VERSION 5.7 ;
  NOWIREEXTENSIONATPIN ON ;
  DIVIDERCHAR "/" ;
  BUSBITCHARS "[]" ;
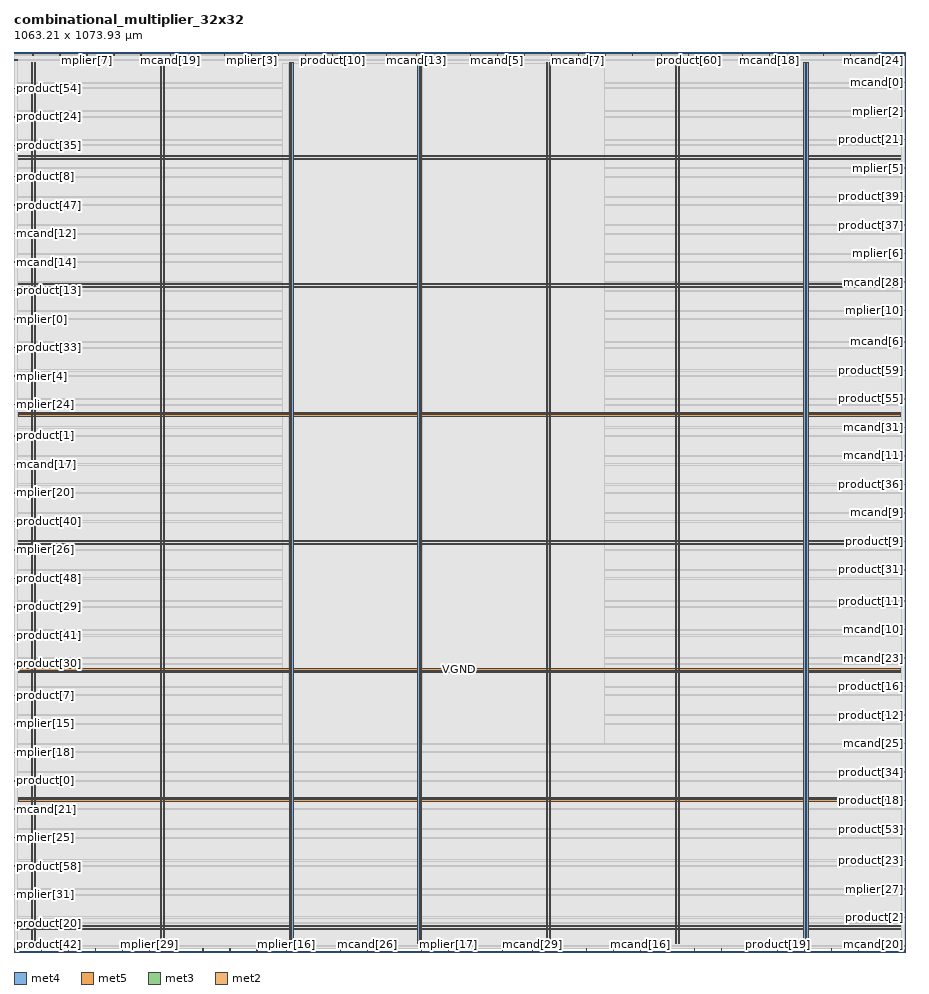
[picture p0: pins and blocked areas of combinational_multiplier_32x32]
MACRO combinational_multiplier_32x32
  CLASS BLOCK ;
  FOREIGN combinational_multiplier_32x32 ;
  ORIGIN 0.000 0.000 ;
  SIZE 1063.210 BY 1073.930 ;
  PIN VGND
    DIRECTION INOUT ;
    USE GROUND ;
    PORT
      LAYER met4 ;
        RECT 24.340 10.640 25.940 1061.040 ;
    END
    PORT
      LAYER met4 ;
        RECT 177.940 10.640 179.540 1061.040 ;
    END
    PORT
      LAYER met4 ;
        RECT 331.540 10.640 333.140 1061.040 ;
    END
    PORT
      LAYER met4 ;
        RECT 485.140 10.640 486.740 1061.040 ;
    END
    PORT
      LAYER met4 ;
        RECT 638.740 10.640 640.340 1061.040 ;
    END
    PORT
      LAYER met4 ;
        RECT 792.340 10.640 793.940 1061.040 ;
    END
    PORT
      LAYER met4 ;
        RECT 945.940 10.640 947.540 1061.040 ;
    END
    PORT
      LAYER met5 ;
        RECT 5.280 30.030 1057.780 31.630 ;
    END
    PORT
      LAYER met5 ;
        RECT 5.280 183.210 1057.780 184.810 ;
    END
    PORT
      LAYER met5 ;
        RECT 5.280 336.390 1057.780 337.990 ;
    END
    PORT
      LAYER met5 ;
        RECT 5.280 489.570 1057.780 491.170 ;
    END
    PORT
      LAYER met5 ;
        RECT 5.280 642.750 1057.780 644.350 ;
    END
    PORT
      LAYER met5 ;
        RECT 5.280 795.930 1057.780 797.530 ;
    END
    PORT
      LAYER met5 ;
        RECT 5.280 949.110 1057.780 950.710 ;
    END
  END VGND
  PIN VPWR
    DIRECTION INOUT ;
    USE POWER ;
    PORT
      LAYER met4 ;
        RECT 21.040 10.640 22.640 1061.040 ;
    END
    PORT
      LAYER met4 ;
        RECT 174.640 10.640 176.240 1061.040 ;
    END
    PORT
      LAYER met4 ;
        RECT 328.240 10.640 329.840 1061.040 ;
    END
    PORT
      LAYER met4 ;
        RECT 481.840 10.640 483.440 1061.040 ;
    END
    PORT
      LAYER met4 ;
        RECT 635.440 10.640 637.040 1061.040 ;
    END
    PORT
      LAYER met4 ;
        RECT 789.040 10.640 790.640 1061.040 ;
    END
    PORT
      LAYER met4 ;
        RECT 942.640 10.640 944.240 1061.040 ;
    END
    PORT
      LAYER met5 ;
        RECT 5.280 26.730 1057.780 28.330 ;
    END
    PORT
      LAYER met5 ;
        RECT 5.280 179.910 1057.780 181.510 ;
    END
    PORT
      LAYER met5 ;
        RECT 5.280 333.090 1057.780 334.690 ;
    END
    PORT
      LAYER met5 ;
        RECT 5.280 486.270 1057.780 487.870 ;
    END
    PORT
      LAYER met5 ;
        RECT 5.280 639.450 1057.780 641.050 ;
    END
    PORT
      LAYER met5 ;
        RECT 5.280 792.630 1057.780 794.230 ;
    END
    PORT
      LAYER met5 ;
        RECT 5.280 945.810 1057.780 947.410 ;
    END
  END VPWR
  PIN mcand[0]
    DIRECTION INPUT ;
    USE SIGNAL ;
    ANTENNAGATEAREA 0.990000 ;
    PORT
      LAYER met3 ;
        RECT 1059.210 1037.040 1063.210 1037.640 ;
    END
  END mcand[0]
  PIN mcand[10]
    DIRECTION INPUT ;
    USE SIGNAL ;
    ANTENNAGATEAREA 0.742500 ;
    PORT
      LAYER met3 ;
        RECT 1059.210 384.240 1063.210 384.840 ;
    END
  END mcand[10]
  PIN mcand[11]
    DIRECTION INPUT ;
    USE SIGNAL ;
    ANTENNAGATEAREA 0.742500 ;
    PORT
      LAYER met3 ;
        RECT 1059.210 591.640 1063.210 592.240 ;
    END
  END mcand[11]
  PIN mcand[12]
    DIRECTION INPUT ;
    USE SIGNAL ;
    ANTENNAGATEAREA 0.426000 ;
    PORT
      LAYER met3 ;
        RECT 0.000 856.840 4.000 857.440 ;
    END
  END mcand[12]
  PIN mcand[13]
    DIRECTION INPUT ;
    USE SIGNAL ;
    ANTENNAGATEAREA 0.742500 ;
    PORT
      LAYER met2 ;
        RECT 479.870 1069.930 480.150 1073.930 ;
    END
  END mcand[13]
  PIN mcand[14]
    DIRECTION INPUT ;
    USE SIGNAL ;
    ANTENNAGATEAREA 0.742500 ;
    PORT
      LAYER met3 ;
        RECT 0.000 822.840 4.000 823.440 ;
    END
  END mcand[14]
  PIN mcand[15]
    DIRECTION INPUT ;
    USE SIGNAL ;
    ANTENNAGATEAREA 0.247500 ;
    PORT
      LAYER met2 ;
        RECT 512.070 1069.930 512.350 1073.930 ;
    END
  END mcand[15]
  PIN mcand[16]
    DIRECTION INPUT ;
    USE SIGNAL ;
    ANTENNAGATEAREA 0.426000 ;
    PORT
      LAYER met2 ;
        RECT 747.130 0.000 747.410 4.000 ;
    END
  END mcand[16]
  PIN mcand[17]
    DIRECTION INPUT ;
    USE SIGNAL ;
    ANTENNAGATEAREA 0.495000 ;
    PORT
      LAYER met3 ;
        RECT 0.000 581.440 4.000 582.040 ;
    END
  END mcand[17]
  PIN mcand[18]
    DIRECTION INPUT ;
    USE SIGNAL ;
    ANTENNAGATEAREA 0.742500 ;
    PORT
      LAYER met2 ;
        RECT 901.690 1069.930 901.970 1073.930 ;
    END
  END mcand[18]
  PIN mcand[19]
    DIRECTION INPUT ;
    USE SIGNAL ;
    ANTENNAGATEAREA 0.742500 ;
    PORT
      LAYER met2 ;
        RECT 186.850 1069.930 187.130 1073.930 ;
    END
  END mcand[19]
  PIN mcand[1]
    DIRECTION INPUT ;
    USE SIGNAL ;
    ANTENNAGATEAREA 0.742500 ;
    PORT
      LAYER met2 ;
        RECT 933.890 1069.930 934.170 1073.930 ;
    END
  END mcand[1]
  PIN mcand[20]
    DIRECTION INPUT ;
    USE SIGNAL ;
    ANTENNAGATEAREA 0.852000 ;
    PORT
      LAYER met2 ;
        RECT 1040.150 0.000 1040.430 4.000 ;
    END
  END mcand[20]
  PIN mcand[21]
    DIRECTION INPUT ;
    USE SIGNAL ;
    ANTENNAGATEAREA 0.852000 ;
    PORT
      LAYER met3 ;
        RECT 0.000 170.040 4.000 170.640 ;
    END
  END mcand[21]
  PIN mcand[22]
    DIRECTION INPUT ;
    USE SIGNAL ;
    ANTENNAGATEAREA 0.426000 ;
    PORT
      LAYER met2 ;
        RECT 257.690 0.000 257.970 4.000 ;
    END
  END mcand[22]
  PIN mcand[23]
    DIRECTION INPUT ;
    USE SIGNAL ;
    ANTENNAGATEAREA 0.742500 ;
    PORT
      LAYER met3 ;
        RECT 1059.210 350.240 1063.210 350.840 ;
    END
  END mcand[23]
  PIN mcand[24]
    DIRECTION INPUT ;
    USE SIGNAL ;
    ANTENNAGATEAREA 0.742500 ;
    PORT
      LAYER met2 ;
        RECT 1062.690 1069.930 1062.970 1073.930 ;
    END
  END mcand[24]
  PIN mcand[25]
    DIRECTION INPUT ;
    USE SIGNAL ;
    ANTENNAGATEAREA 0.495000 ;
    PORT
      LAYER met3 ;
        RECT 1059.210 248.240 1063.210 248.840 ;
    END
  END mcand[25]
  PIN mcand[26]
    DIRECTION INPUT ;
    USE SIGNAL ;
    ANTENNAGATEAREA 0.852000 ;
    PORT
      LAYER met2 ;
        RECT 421.910 0.000 422.190 4.000 ;
    END
  END mcand[26]
  PIN mcand[27]
    DIRECTION INPUT ;
    USE SIGNAL ;
    ANTENNAGATEAREA 0.247500 ;
    PORT
      LAYER met2 ;
        RECT 444.450 1069.930 444.730 1073.930 ;
    END
  END mcand[27]
  PIN mcand[28]
    DIRECTION INPUT ;
    USE SIGNAL ;
    ANTENNAGATEAREA 0.247500 ;
    PORT
      LAYER met3 ;
        RECT 1059.210 799.040 1063.210 799.640 ;
    END
  END mcand[28]
  PIN mcand[29]
    DIRECTION INPUT ;
    USE SIGNAL ;
    ANTENNAGATEAREA 0.742500 ;
    PORT
      LAYER met2 ;
        RECT 618.330 0.000 618.610 4.000 ;
    END
  END mcand[29]
  PIN mcand[2]
    DIRECTION INPUT ;
    USE SIGNAL ;
    ANTENNAGATEAREA 0.247500 ;
    PORT
      LAYER met2 ;
        RECT 289.890 0.000 290.170 4.000 ;
    END
  END mcand[2]
  PIN mcand[30]
    DIRECTION INPUT ;
    USE SIGNAL ;
    ANTENNAGATEAREA 0.213000 ;
    PORT
      LAYER met2 ;
        RECT 251.250 1069.930 251.530 1073.930 ;
    END
  END mcand[30]
  PIN mcand[31]
    DIRECTION INPUT ;
    USE SIGNAL ;
    ANTENNAGATEAREA 0.213000 ;
    PORT
      LAYER met3 ;
        RECT 1059.210 625.640 1063.210 626.240 ;
    END
  END mcand[31]
  PIN mcand[3]
    DIRECTION INPUT ;
    USE SIGNAL ;
    ANTENNAGATEAREA 0.495000 ;
    PORT
      LAYER met2 ;
        RECT 650.530 0.000 650.810 4.000 ;
    END
  END mcand[3]
  PIN mcand[4]
    DIRECTION INPUT ;
    USE SIGNAL ;
    ANTENNAGATEAREA 0.990000 ;
    PORT
      LAYER met2 ;
        RECT 998.290 1069.930 998.570 1073.930 ;
    END
  END mcand[4]
  PIN mcand[5]
    DIRECTION INPUT ;
    USE SIGNAL ;
    ANTENNAGATEAREA 0.247500 ;
    PORT
      LAYER met2 ;
        RECT 576.470 1069.930 576.750 1073.930 ;
    END
  END mcand[5]
  PIN mcand[6]
    DIRECTION INPUT ;
    USE SIGNAL ;
    ANTENNAGATEAREA 0.990000 ;
    PORT
      LAYER met3 ;
        RECT 1059.210 727.640 1063.210 728.240 ;
    END
  END mcand[6]
  PIN mcand[7]
    DIRECTION INPUT ;
    USE SIGNAL ;
    ANTENNAGATEAREA 0.990000 ;
    PORT
      LAYER met2 ;
        RECT 673.070 1069.930 673.350 1073.930 ;
    END
  END mcand[7]
  PIN mcand[8]
    DIRECTION INPUT ;
    USE SIGNAL ;
    ANTENNAGATEAREA 0.852000 ;
    PORT
      LAYER met2 ;
        RECT 1007.950 0.000 1008.230 4.000 ;
    END
  END mcand[8]
  PIN mcand[9]
    DIRECTION INPUT ;
    USE SIGNAL ;
    ANTENNAGATEAREA 0.495000 ;
    PORT
      LAYER met3 ;
        RECT 1059.210 523.640 1063.210 524.240 ;
    END
  END mcand[9]
  PIN mplier[0]
    DIRECTION INPUT ;
    USE SIGNAL ;
    ANTENNAGATEAREA 0.742500 ;
    PORT
      LAYER met3 ;
        RECT 0.000 754.840 4.000 755.440 ;
    END
  END mplier[0]
  PIN mplier[10]
    DIRECTION INPUT ;
    USE SIGNAL ;
    ANTENNAGATEAREA 0.742500 ;
    PORT
      LAYER met3 ;
        RECT 1059.210 765.040 1063.210 765.640 ;
    END
  END mplier[10]
  PIN mplier[11]
    DIRECTION INPUT ;
    USE SIGNAL ;
    ANTENNAGATEAREA 0.742500 ;
    PORT
      LAYER met2 ;
        RECT 454.110 0.000 454.390 4.000 ;
    END
  END mplier[11]
  PIN mplier[12]
    DIRECTION INPUT ;
    USE SIGNAL ;
    ANTENNAGATEAREA 0.495000 ;
    PORT
      LAYER met2 ;
        RECT 1030.490 1069.930 1030.770 1073.930 ;
    END
  END mplier[12]
  PIN mplier[13]
    DIRECTION INPUT ;
    USE SIGNAL ;
    ANTENNAGATEAREA 0.742500 ;
    PORT
      LAYER met2 ;
        RECT 875.930 0.000 876.210 4.000 ;
    END
  END mplier[13]
  PIN mplier[14]
    DIRECTION INPUT ;
    USE SIGNAL ;
    ANTENNAGATEAREA 0.742500 ;
    PORT
      LAYER met2 ;
        RECT 811.530 0.000 811.810 4.000 ;
    END
  END mplier[14]
  PIN mplier[15]
    DIRECTION INPUT ;
    USE SIGNAL ;
    ANTENNAGATEAREA 0.247500 ;
    PORT
      LAYER met3 ;
        RECT 0.000 272.040 4.000 272.640 ;
    END
  END mplier[15]
  PIN mplier[16]
    DIRECTION INPUT ;
    USE SIGNAL ;
    ANTENNAGATEAREA 0.426000 ;
    PORT
      LAYER met2 ;
        RECT 325.310 0.000 325.590 4.000 ;
    END
  END mplier[16]
  PIN mplier[17]
    DIRECTION INPUT ;
    USE SIGNAL ;
    ANTENNAGATEAREA 0.247500 ;
    PORT
      LAYER met2 ;
        RECT 518.510 0.000 518.790 4.000 ;
    END
  END mplier[17]
  PIN mplier[18]
    DIRECTION INPUT ;
    USE SIGNAL ;
    ANTENNAGATEAREA 0.426000 ;
    PORT
      LAYER met3 ;
        RECT 0.000 238.040 4.000 238.640 ;
    END
  END mplier[18]
  PIN mplier[19]
    DIRECTION INPUT ;
    USE SIGNAL ;
    ANTENNAGATEAREA 0.495000 ;
    PORT
      LAYER met2 ;
        RECT 608.670 1069.930 608.950 1073.930 ;
    END
  END mplier[19]
  PIN mplier[1]
    DIRECTION INPUT ;
    USE SIGNAL ;
    ANTENNAGATEAREA 0.742500 ;
    PORT
      LAYER met2 ;
        RECT 32.290 0.000 32.570 4.000 ;
    END
  END mplier[1]
  PIN mplier[20]
    DIRECTION INPUT ;
    USE SIGNAL ;
    ANTENNAGATEAREA 0.247500 ;
    PORT
      LAYER met3 ;
        RECT 0.000 547.440 4.000 548.040 ;
    END
  END mplier[20]
  PIN mplier[21]
    DIRECTION INPUT ;
    USE SIGNAL ;
    ANTENNAGATEAREA 0.742500 ;
    PORT
      LAYER met2 ;
        RECT 119.230 1069.930 119.510 1073.930 ;
    END
  END mplier[21]
  PIN mplier[22]
    DIRECTION INPUT ;
    USE SIGNAL ;
    ANTENNAGATEAREA 0.742500 ;
    PORT
      LAYER met2 ;
        RECT 737.470 1069.930 737.750 1073.930 ;
    END
  END mplier[22]
  PIN mplier[23]
    DIRECTION INPUT ;
    USE SIGNAL ;
    ANTENNAGATEAREA 0.247500 ;
    PORT
      LAYER met2 ;
        RECT 315.650 1069.930 315.930 1073.930 ;
    END
  END mplier[23]
  PIN mplier[24]
    DIRECTION INPUT ;
    USE SIGNAL ;
    ANTENNAGATEAREA 0.247500 ;
    PORT
      LAYER met3 ;
        RECT 0.000 652.840 4.000 653.440 ;
    END
  END mplier[24]
  PIN mplier[25]
    DIRECTION INPUT ;
    USE SIGNAL ;
    ANTENNAGATEAREA 0.426000 ;
    PORT
      LAYER met3 ;
        RECT 0.000 136.040 4.000 136.640 ;
    END
  END mplier[25]
  PIN mplier[26]
    DIRECTION INPUT ;
    USE SIGNAL ;
    ANTENNAGATEAREA 0.426000 ;
    PORT
      LAYER met3 ;
        RECT 0.000 479.440 4.000 480.040 ;
    END
  END mplier[26]
  PIN mplier[27]
    DIRECTION INPUT ;
    USE SIGNAL ;
    ANTENNAGATEAREA 0.742500 ;
    PORT
      LAYER met3 ;
        RECT 1059.210 74.840 1063.210 75.440 ;
    END
  END mplier[27]
  PIN mplier[28]
    DIRECTION INPUT ;
    USE SIGNAL ;
    ANTENNAGATEAREA 0.495000 ;
    PORT
      LAYER met2 ;
        RECT 389.710 0.000 389.990 4.000 ;
    END
  END mplier[28]
  PIN mplier[29]
    DIRECTION INPUT ;
    USE SIGNAL ;
    ANTENNAGATEAREA 0.247500 ;
    PORT
      LAYER met2 ;
        RECT 161.090 0.000 161.370 4.000 ;
    END
  END mplier[29]
  PIN mplier[2]
    DIRECTION INPUT ;
    USE SIGNAL ;
    ANTENNAGATEAREA 0.742500 ;
    PORT
      LAYER met3 ;
        RECT 1059.210 1003.040 1063.210 1003.640 ;
    END
  END mplier[2]
  PIN mplier[30]
    DIRECTION INPUT ;
    USE SIGNAL ;
    ANTENNAGATEAREA 0.742500 ;
    PORT
      LAYER met3 ;
        RECT 0.000 1064.240 4.000 1064.840 ;
    END
  END mplier[30]
  PIN mplier[31]
    DIRECTION INPUT ;
    USE SIGNAL ;
    ANTENNAGATEAREA 0.426000 ;
    PORT
      LAYER met3 ;
        RECT 0.000 68.040 4.000 68.640 ;
    END
  END mplier[31]
  PIN mplier[3]
    DIRECTION INPUT ;
    USE SIGNAL ;
    ANTENNAGATEAREA 0.742500 ;
    PORT
      LAYER met2 ;
        RECT 283.450 1069.930 283.730 1073.930 ;
    END
  END mplier[3]
  PIN mplier[4]
    DIRECTION INPUT ;
    USE SIGNAL ;
    ANTENNAGATEAREA 0.426000 ;
    PORT
      LAYER met3 ;
        RECT 0.000 686.840 4.000 687.440 ;
    END
  END mplier[4]
  PIN mplier[5]
    DIRECTION INPUT ;
    USE SIGNAL ;
    ANTENNAGATEAREA 0.426000 ;
    PORT
      LAYER met3 ;
        RECT 1059.210 935.040 1063.210 935.640 ;
    END
  END mplier[5]
  PIN mplier[6]
    DIRECTION INPUT ;
    USE SIGNAL ;
    ANTENNAGATEAREA 0.247500 ;
    PORT
      LAYER met3 ;
        RECT 1059.210 833.040 1063.210 833.640 ;
    END
  END mplier[6]
  PIN mplier[7]
    DIRECTION INPUT ;
    USE SIGNAL ;
    ANTENNAGATEAREA 0.742500 ;
    PORT
      LAYER met2 ;
        RECT 87.030 1069.930 87.310 1073.930 ;
    END
  END mplier[7]
  PIN mplier[8]
    DIRECTION INPUT ;
    USE SIGNAL ;
    ANTENNAGATEAREA 0.495000 ;
    PORT
      LAYER met2 ;
        RECT 151.430 1069.930 151.710 1073.930 ;
    END
  END mplier[8]
  PIN mplier[9]
    DIRECTION INPUT ;
    USE SIGNAL ;
    ANTENNAGATEAREA 0.852000 ;
    PORT
      LAYER met2 ;
        RECT 128.890 0.000 129.170 4.000 ;
    END
  END mplier[9]
  PIN product[0]
    DIRECTION OUTPUT TRISTATE ;
    USE SIGNAL ;
    ANTENNADIFFAREA 0.795200 ;
    PORT
      LAYER met3 ;
        RECT 0.000 204.040 4.000 204.640 ;
    END
  END product[0]
  PIN product[10]
    DIRECTION OUTPUT TRISTATE ;
    USE SIGNAL ;
    ANTENNADIFFAREA 0.795200 ;
    PORT
      LAYER met2 ;
        RECT 380.050 1069.930 380.330 1073.930 ;
    END
  END product[10]
  PIN product[11]
    DIRECTION OUTPUT TRISTATE ;
    USE SIGNAL ;
    ANTENNADIFFAREA 0.795200 ;
    PORT
      LAYER met3 ;
        RECT 1059.210 418.240 1063.210 418.840 ;
    END
  END product[11]
  PIN product[12]
    DIRECTION OUTPUT TRISTATE ;
    USE SIGNAL ;
    ANTENNADIFFAREA 0.795200 ;
    PORT
      LAYER met3 ;
        RECT 1059.210 282.240 1063.210 282.840 ;
    END
  END product[12]
  PIN product[13]
    DIRECTION OUTPUT TRISTATE ;
    USE SIGNAL ;
    ANTENNADIFFAREA 0.795200 ;
    PORT
      LAYER met3 ;
        RECT 0.000 788.840 4.000 789.440 ;
    END
  END product[13]
  PIN product[14]
    DIRECTION OUTPUT TRISTATE ;
    USE SIGNAL ;
    ANTENNADIFFAREA 0.795200 ;
    PORT
      LAYER met2 ;
        RECT 412.250 1069.930 412.530 1073.930 ;
    END
  END product[14]
  PIN product[15]
    DIRECTION OUTPUT TRISTATE ;
    USE SIGNAL ;
    ANTENNADIFFAREA 0.795200 ;
    PORT
      LAYER met3 ;
        RECT 1059.210 6.840 1063.210 7.440 ;
    END
  END product[15]
  PIN product[16]
    DIRECTION OUTPUT TRISTATE ;
    USE SIGNAL ;
    ANTENNADIFFAREA 0.795200 ;
    PORT
      LAYER met3 ;
        RECT 1059.210 316.240 1063.210 316.840 ;
    END
  END product[16]
  PIN product[17]
    DIRECTION OUTPUT TRISTATE ;
    USE SIGNAL ;
    ANTENNADIFFAREA 0.795200 ;
    PORT
      LAYER met2 ;
        RECT 837.290 1069.930 837.570 1073.930 ;
    END
  END product[17]
  PIN product[18]
    DIRECTION OUTPUT TRISTATE ;
    USE SIGNAL ;
    ANTENNADIFFAREA 0.795200 ;
    PORT
      LAYER met3 ;
        RECT 1059.210 180.240 1063.210 180.840 ;
    END
  END product[18]
  PIN product[19]
    DIRECTION OUTPUT TRISTATE ;
    USE SIGNAL ;
    ANTENNADIFFAREA 0.795200 ;
    PORT
      LAYER met2 ;
        RECT 911.350 0.000 911.630 4.000 ;
    END
  END product[19]
  PIN product[1]
    DIRECTION OUTPUT TRISTATE ;
    USE SIGNAL ;
    ANTENNADIFFAREA 0.795200 ;
    PORT
      LAYER met3 ;
        RECT 0.000 615.440 4.000 616.040 ;
    END
  END product[1]
  PIN product[20]
    DIRECTION OUTPUT TRISTATE ;
    USE SIGNAL ;
    ANTENNADIFFAREA 0.795200 ;
    PORT
      LAYER met3 ;
        RECT 0.000 34.040 4.000 34.640 ;
    END
  END product[20]
  PIN product[21]
    DIRECTION OUTPUT TRISTATE ;
    USE SIGNAL ;
    ANTENNADIFFAREA 0.795200 ;
    PORT
      LAYER met3 ;
        RECT 1059.210 969.040 1063.210 969.640 ;
    END
  END product[21]
  PIN product[22]
    DIRECTION OUTPUT TRISTATE ;
    USE SIGNAL ;
    ANTENNADIFFAREA 0.795200 ;
    PORT
      LAYER met2 ;
        RECT 225.490 0.000 225.770 4.000 ;
    END
  END product[22]
  PIN product[23]
    DIRECTION OUTPUT TRISTATE ;
    USE SIGNAL ;
    ANTENNADIFFAREA 0.795200 ;
    PORT
      LAYER met3 ;
        RECT 1059.210 108.840 1063.210 109.440 ;
    END
  END product[23]
  PIN product[24]
    DIRECTION OUTPUT TRISTATE ;
    USE SIGNAL ;
    ANTENNADIFFAREA 0.795200 ;
    PORT
      LAYER met3 ;
        RECT 0.000 996.240 4.000 996.840 ;
    END
  END product[24]
  PIN product[25]
    DIRECTION OUTPUT TRISTATE ;
    USE SIGNAL ;
    ANTENNADIFFAREA 0.795200 ;
    PORT
      LAYER met2 ;
        RECT 975.750 0.000 976.030 4.000 ;
    END
  END product[25]
  PIN product[26]
    DIRECTION OUTPUT TRISTATE ;
    USE SIGNAL ;
    ANTENNADIFFAREA 0.795200 ;
    PORT
      LAYER met2 ;
        RECT 544.270 1069.930 544.550 1073.930 ;
    END
  END product[26]
  PIN product[27]
    DIRECTION OUTPUT TRISTATE ;
    USE SIGNAL ;
    ANTENNADIFFAREA 0.795200 ;
    PORT
      LAYER met2 ;
        RECT 779.330 0.000 779.610 4.000 ;
    END
  END product[27]
  PIN product[28]
    DIRECTION OUTPUT TRISTATE ;
    USE SIGNAL ;
    ANTENNADIFFAREA 0.795200 ;
    PORT
      LAYER met2 ;
        RECT 96.690 0.000 96.970 4.000 ;
    END
  END product[28]
  PIN product[29]
    DIRECTION OUTPUT TRISTATE ;
    USE SIGNAL ;
    ANTENNADIFFAREA 0.795200 ;
    PORT
      LAYER met3 ;
        RECT 0.000 411.440 4.000 412.040 ;
    END
  END product[29]
  PIN product[2]
    DIRECTION OUTPUT TRISTATE ;
    USE SIGNAL ;
    ANTENNADIFFAREA 0.795200 ;
    PORT
      LAYER met3 ;
        RECT 1059.210 40.840 1063.210 41.440 ;
    END
  END product[2]
  PIN product[30]
    DIRECTION OUTPUT TRISTATE ;
    USE SIGNAL ;
    ANTENNADIFFAREA 0.795200 ;
    PORT
      LAYER met3 ;
        RECT 0.000 343.440 4.000 344.040 ;
    END
  END product[30]
  PIN product[31]
    DIRECTION OUTPUT TRISTATE ;
    USE SIGNAL ;
    ANTENNADIFFAREA 0.795200 ;
    PORT
      LAYER met3 ;
        RECT 1059.210 455.640 1063.210 456.240 ;
    END
  END product[31]
  PIN product[32]
    DIRECTION OUTPUT TRISTATE ;
    USE SIGNAL ;
    ANTENNADIFFAREA 0.795200 ;
    PORT
      LAYER met2 ;
        RECT 843.730 0.000 844.010 4.000 ;
    END
  END product[32]
  PIN product[33]
    DIRECTION OUTPUT TRISTATE ;
    USE SIGNAL ;
    ANTENNADIFFAREA 0.795200 ;
    PORT
      LAYER met3 ;
        RECT 0.000 720.840 4.000 721.440 ;
    END
  END product[33]
  PIN product[34]
    DIRECTION OUTPUT TRISTATE ;
    USE SIGNAL ;
    ANTENNADIFFAREA 0.795200 ;
    PORT
      LAYER met3 ;
        RECT 1059.210 214.240 1063.210 214.840 ;
    END
  END product[34]
  PIN product[35]
    DIRECTION OUTPUT TRISTATE ;
    USE SIGNAL ;
    ANTENNADIFFAREA 0.795200 ;
    PORT
      LAYER met3 ;
        RECT 0.000 962.240 4.000 962.840 ;
    END
  END product[35]
  PIN product[36]
    DIRECTION OUTPUT TRISTATE ;
    USE SIGNAL ;
    ANTENNADIFFAREA 0.795200 ;
    PORT
      LAYER met3 ;
        RECT 1059.210 557.640 1063.210 558.240 ;
    END
  END product[36]
  PIN product[37]
    DIRECTION OUTPUT TRISTATE ;
    USE SIGNAL ;
    ANTENNADIFFAREA 0.795200 ;
    PORT
      LAYER met3 ;
        RECT 1059.210 867.040 1063.210 867.640 ;
    END
  END product[37]
  PIN product[38]
    DIRECTION OUTPUT TRISTATE ;
    USE SIGNAL ;
    ANTENNADIFFAREA 0.795200 ;
    PORT
      LAYER met2 ;
        RECT 943.550 0.000 943.830 4.000 ;
    END
  END product[38]
  PIN product[39]
    DIRECTION OUTPUT TRISTATE ;
    USE SIGNAL ;
    ANTENNADIFFAREA 0.795200 ;
    PORT
      LAYER met3 ;
        RECT 1059.210 901.040 1063.210 901.640 ;
    END
  END product[39]
  PIN product[3]
    DIRECTION OUTPUT TRISTATE ;
    USE SIGNAL ;
    ANTENNADIFFAREA 0.795200 ;
    PORT
      LAYER met2 ;
        RECT 550.710 0.000 550.990 4.000 ;
    END
  END product[3]
  PIN product[40]
    DIRECTION OUTPUT TRISTATE ;
    USE SIGNAL ;
    ANTENNADIFFAREA 0.795200 ;
    PORT
      LAYER met3 ;
        RECT 0.000 513.440 4.000 514.040 ;
    END
  END product[40]
  PIN product[41]
    DIRECTION OUTPUT TRISTATE ;
    USE SIGNAL ;
    ANTENNADIFFAREA 0.795200 ;
    PORT
      LAYER met3 ;
        RECT 0.000 377.440 4.000 378.040 ;
    END
  END product[41]
  PIN product[42]
    DIRECTION OUTPUT TRISTATE ;
    USE SIGNAL ;
    ANTENNADIFFAREA 0.795200 ;
    PORT
      LAYER met2 ;
        RECT 0.090 0.000 0.370 4.000 ;
    END
  END product[42]
  PIN product[43]
    DIRECTION OUTPUT TRISTATE ;
    USE SIGNAL ;
    ANTENNADIFFAREA 0.795200 ;
    PORT
      LAYER met2 ;
        RECT 682.730 0.000 683.010 4.000 ;
    END
  END product[43]
  PIN product[44]
    DIRECTION OUTPUT TRISTATE ;
    USE SIGNAL ;
    ANTENNADIFFAREA 0.795200 ;
    PORT
      LAYER met2 ;
        RECT 22.630 1069.930 22.910 1073.930 ;
    END
  END product[44]
  PIN product[45]
    DIRECTION OUTPUT TRISTATE ;
    USE SIGNAL ;
    ANTENNADIFFAREA 0.795200 ;
    PORT
      LAYER met2 ;
        RECT 347.850 1069.930 348.130 1073.930 ;
    END
  END product[45]
  PIN product[46]
    DIRECTION OUTPUT TRISTATE ;
    USE SIGNAL ;
    ANTENNADIFFAREA 0.795200 ;
    PORT
      LAYER met2 ;
        RECT 705.270 1069.930 705.550 1073.930 ;
    END
  END product[46]
  PIN product[47]
    DIRECTION OUTPUT TRISTATE ;
    USE SIGNAL ;
    ANTENNADIFFAREA 0.795200 ;
    PORT
      LAYER met3 ;
        RECT 0.000 890.840 4.000 891.440 ;
    END
  END product[47]
  PIN product[48]
    DIRECTION OUTPUT TRISTATE ;
    USE SIGNAL ;
    ANTENNADIFFAREA 0.795200 ;
    PORT
      LAYER met3 ;
        RECT 0.000 445.440 4.000 446.040 ;
    END
  END product[48]
  PIN product[49]
    DIRECTION OUTPUT TRISTATE ;
    USE SIGNAL ;
    ANTENNADIFFAREA 0.795200 ;
    PORT
      LAYER met2 ;
        RECT 64.490 0.000 64.770 4.000 ;
    END
  END product[49]
  PIN product[4]
    DIRECTION OUTPUT TRISTATE ;
    USE SIGNAL ;
    ANTENNADIFFAREA 0.795200 ;
    PORT
      LAYER met2 ;
        RECT 869.490 1069.930 869.770 1073.930 ;
    END
  END product[4]
  PIN product[50]
    DIRECTION OUTPUT TRISTATE ;
    USE SIGNAL ;
    ANTENNADIFFAREA 0.795200 ;
    PORT
      LAYER met2 ;
        RECT 640.870 1069.930 641.150 1073.930 ;
    END
  END product[50]
  PIN product[51]
    DIRECTION OUTPUT TRISTATE ;
    USE SIGNAL ;
    ANTENNADIFFAREA 0.795200 ;
    PORT
      LAYER met2 ;
        RECT 486.310 0.000 486.590 4.000 ;
    END
  END product[51]
  PIN product[52]
    DIRECTION OUTPUT TRISTATE ;
    USE SIGNAL ;
    ANTENNADIFFAREA 0.795200 ;
    PORT
      LAYER met2 ;
        RECT 966.090 1069.930 966.370 1073.930 ;
    END
  END product[52]
  PIN product[53]
    DIRECTION OUTPUT TRISTATE ;
    USE SIGNAL ;
    ANTENNADIFFAREA 0.795200 ;
    PORT
      LAYER met3 ;
        RECT 1059.210 146.240 1063.210 146.840 ;
    END
  END product[53]
  PIN product[54]
    DIRECTION OUTPUT TRISTATE ;
    USE SIGNAL ;
    ANTENNADIFFAREA 0.795200 ;
    PORT
      LAYER met3 ;
        RECT 0.000 1030.240 4.000 1030.840 ;
    END
  END product[54]
  PIN product[55]
    DIRECTION OUTPUT TRISTATE ;
    USE SIGNAL ;
    ANTENNADIFFAREA 0.795200 ;
    PORT
      LAYER met3 ;
        RECT 1059.210 659.640 1063.210 660.240 ;
    END
  END product[55]
  PIN product[56]
    DIRECTION OUTPUT TRISTATE ;
    USE SIGNAL ;
    ANTENNADIFFAREA 0.795200 ;
    PORT
      LAYER met2 ;
        RECT 193.290 0.000 193.570 4.000 ;
    END
  END product[56]
  PIN product[57]
    DIRECTION OUTPUT TRISTATE ;
    USE SIGNAL ;
    ANTENNADIFFAREA 0.795200 ;
    PORT
      LAYER met2 ;
        RECT 357.510 0.000 357.790 4.000 ;
    END
  END product[57]
  PIN product[58]
    DIRECTION OUTPUT TRISTATE ;
    USE SIGNAL ;
    ANTENNADIFFAREA 0.891000 ;
    PORT
      LAYER met3 ;
        RECT 0.000 102.040 4.000 102.640 ;
    END
  END product[58]
  PIN product[59]
    DIRECTION OUTPUT TRISTATE ;
    USE SIGNAL ;
    ANTENNADIFFAREA 1.336500 ;
    PORT
      LAYER met3 ;
        RECT 1059.210 693.640 1063.210 694.240 ;
    END
  END product[59]
  PIN product[5]
    DIRECTION OUTPUT TRISTATE ;
    USE SIGNAL ;
    ANTENNADIFFAREA 0.795200 ;
    PORT
      LAYER met2 ;
        RECT 582.910 0.000 583.190 4.000 ;
    END
  END product[5]
  PIN product[60]
    DIRECTION OUTPUT TRISTATE ;
    USE SIGNAL ;
    ANTENNADIFFAREA 0.795200 ;
    PORT
      LAYER met2 ;
        RECT 805.090 1069.930 805.370 1073.930 ;
    END
  END product[60]
  PIN product[61]
    DIRECTION OUTPUT TRISTATE ;
    USE SIGNAL ;
    ANTENNADIFFAREA 0.795200 ;
    PORT
      LAYER met2 ;
        RECT 772.890 1069.930 773.170 1073.930 ;
    END
  END product[61]
  PIN product[62]
    DIRECTION OUTPUT TRISTATE ;
    USE SIGNAL ;
    ANTENNADIFFAREA 1.336500 ;
    PORT
      LAYER met2 ;
        RECT 54.830 1069.930 55.110 1073.930 ;
    END
  END product[62]
  PIN product[63]
    DIRECTION OUTPUT TRISTATE ;
    USE SIGNAL ;
    ANTENNADIFFAREA 1.782000 ;
    PORT
      LAYER met2 ;
        RECT 219.050 1069.930 219.330 1073.930 ;
    END
  END product[63]
  PIN product[6]
    DIRECTION OUTPUT TRISTATE ;
    USE SIGNAL ;
    ANTENNADIFFAREA 0.795200 ;
    PORT
      LAYER met2 ;
        RECT 714.930 0.000 715.210 4.000 ;
    END
  END product[6]
  PIN product[7]
    DIRECTION OUTPUT TRISTATE ;
    USE SIGNAL ;
    ANTENNADIFFAREA 0.795200 ;
    PORT
      LAYER met3 ;
        RECT 0.000 306.040 4.000 306.640 ;
    END
  END product[7]
  PIN product[8]
    DIRECTION OUTPUT TRISTATE ;
    USE SIGNAL ;
    ANTENNADIFFAREA 0.795200 ;
    PORT
      LAYER met3 ;
        RECT 0.000 924.840 4.000 925.440 ;
    END
  END product[8]
  PIN product[9]
    DIRECTION OUTPUT TRISTATE ;
    USE SIGNAL ;
    ANTENNADIFFAREA 0.795200 ;
    PORT
      LAYER met3 ;
        RECT 1059.210 489.640 1063.210 490.240 ;
    END
  END product[9]
  OBS
      LAYER li1 ;
        RECT 5.520 10.795 1057.540 1060.885 ;
      LAYER met1 ;
        RECT 0.070 7.860 1062.990 1062.460 ;
      LAYER met2 ;
        RECT 0.100 1069.650 22.350 1070.730 ;
        RECT 23.190 1069.650 54.550 1070.730 ;
        RECT 55.390 1069.650 86.750 1070.730 ;
        RECT 87.590 1069.650 118.950 1070.730 ;
        RECT 119.790 1069.650 151.150 1070.730 ;
        RECT 151.990 1069.650 186.570 1070.730 ;
        RECT 187.410 1069.650 218.770 1070.730 ;
        RECT 219.610 1069.650 250.970 1070.730 ;
        RECT 251.810 1069.650 283.170 1070.730 ;
        RECT 284.010 1069.650 315.370 1070.730 ;
        RECT 316.210 1069.650 347.570 1070.730 ;
        RECT 348.410 1069.650 379.770 1070.730 ;
        RECT 380.610 1069.650 411.970 1070.730 ;
        RECT 412.810 1069.650 444.170 1070.730 ;
        RECT 445.010 1069.650 479.590 1070.730 ;
        RECT 480.430 1069.650 511.790 1070.730 ;
        RECT 512.630 1069.650 543.990 1070.730 ;
        RECT 544.830 1069.650 576.190 1070.730 ;
        RECT 577.030 1069.650 608.390 1070.730 ;
        RECT 609.230 1069.650 640.590 1070.730 ;
        RECT 641.430 1069.650 672.790 1070.730 ;
        RECT 673.630 1069.650 704.990 1070.730 ;
        RECT 705.830 1069.650 737.190 1070.730 ;
        RECT 738.030 1069.650 772.610 1070.730 ;
        RECT 773.450 1069.650 804.810 1070.730 ;
        RECT 805.650 1069.650 837.010 1070.730 ;
        RECT 837.850 1069.650 869.210 1070.730 ;
        RECT 870.050 1069.650 901.410 1070.730 ;
        RECT 902.250 1069.650 933.610 1070.730 ;
        RECT 934.450 1069.650 965.810 1070.730 ;
        RECT 966.650 1069.650 998.010 1070.730 ;
        RECT 998.850 1069.650 1030.210 1070.730 ;
        RECT 1031.050 1069.650 1062.410 1070.730 ;
        RECT 0.100 4.280 1062.960 1069.650 ;
        RECT 0.650 3.670 32.010 4.280 ;
        RECT 32.850 3.670 64.210 4.280 ;
        RECT 65.050 3.670 96.410 4.280 ;
        RECT 97.250 3.670 128.610 4.280 ;
        RECT 129.450 3.670 160.810 4.280 ;
        RECT 161.650 3.670 193.010 4.280 ;
        RECT 193.850 3.670 225.210 4.280 ;
        RECT 226.050 3.670 257.410 4.280 ;
        RECT 258.250 3.670 289.610 4.280 ;
        RECT 290.450 3.670 325.030 4.280 ;
        RECT 325.870 3.670 357.230 4.280 ;
        RECT 358.070 3.670 389.430 4.280 ;
        RECT 390.270 3.670 421.630 4.280 ;
        RECT 422.470 3.670 453.830 4.280 ;
        RECT 454.670 3.670 486.030 4.280 ;
        RECT 486.870 3.670 518.230 4.280 ;
        RECT 519.070 3.670 550.430 4.280 ;
        RECT 551.270 3.670 582.630 4.280 ;
        RECT 583.470 3.670 618.050 4.280 ;
        RECT 618.890 3.670 650.250 4.280 ;
        RECT 651.090 3.670 682.450 4.280 ;
        RECT 683.290 3.670 714.650 4.280 ;
        RECT 715.490 3.670 746.850 4.280 ;
        RECT 747.690 3.670 779.050 4.280 ;
        RECT 779.890 3.670 811.250 4.280 ;
        RECT 812.090 3.670 843.450 4.280 ;
        RECT 844.290 3.670 875.650 4.280 ;
        RECT 876.490 3.670 911.070 4.280 ;
        RECT 911.910 3.670 943.270 4.280 ;
        RECT 944.110 3.670 975.470 4.280 ;
        RECT 976.310 3.670 1007.670 4.280 ;
        RECT 1008.510 3.670 1039.870 4.280 ;
        RECT 1040.710 3.670 1062.960 4.280 ;
      LAYER met3 ;
        RECT 4.400 1063.840 1059.210 1064.690 ;
        RECT 3.990 1038.040 1059.210 1063.840 ;
        RECT 3.990 1036.640 1058.810 1038.040 ;
        RECT 3.990 1031.240 1059.210 1036.640 ;
        RECT 4.400 1029.840 1059.210 1031.240 ;
        RECT 3.990 1004.040 1059.210 1029.840 ;
        RECT 3.990 1002.640 1058.810 1004.040 ;
        RECT 3.990 997.240 1059.210 1002.640 ;
        RECT 4.400 995.840 1059.210 997.240 ;
        RECT 3.990 970.040 1059.210 995.840 ;
        RECT 3.990 968.640 1058.810 970.040 ;
        RECT 3.990 963.240 1059.210 968.640 ;
        RECT 4.400 961.840 1059.210 963.240 ;
        RECT 3.990 936.040 1059.210 961.840 ;
        RECT 3.990 934.640 1058.810 936.040 ;
        RECT 3.990 925.840 1059.210 934.640 ;
        RECT 4.400 924.440 1059.210 925.840 ;
        RECT 3.990 902.040 1059.210 924.440 ;
        RECT 3.990 900.640 1058.810 902.040 ;
        RECT 3.990 891.840 1059.210 900.640 ;
        RECT 4.400 890.440 1059.210 891.840 ;
        RECT 3.990 868.040 1059.210 890.440 ;
        RECT 3.990 866.640 1058.810 868.040 ;
        RECT 3.990 857.840 1059.210 866.640 ;
        RECT 4.400 856.440 1059.210 857.840 ;
        RECT 3.990 834.040 1059.210 856.440 ;
        RECT 3.990 832.640 1058.810 834.040 ;
        RECT 3.990 823.840 1059.210 832.640 ;
        RECT 4.400 822.440 1059.210 823.840 ;
        RECT 3.990 800.040 1059.210 822.440 ;
        RECT 3.990 798.640 1058.810 800.040 ;
        RECT 3.990 789.840 1059.210 798.640 ;
        RECT 4.400 788.440 1059.210 789.840 ;
        RECT 3.990 766.040 1059.210 788.440 ;
        RECT 3.990 764.640 1058.810 766.040 ;
        RECT 3.990 755.840 1059.210 764.640 ;
        RECT 4.400 754.440 1059.210 755.840 ;
        RECT 3.990 728.640 1059.210 754.440 ;
        RECT 3.990 727.240 1058.810 728.640 ;
        RECT 3.990 721.840 1059.210 727.240 ;
        RECT 4.400 720.440 1059.210 721.840 ;
        RECT 3.990 694.640 1059.210 720.440 ;
        RECT 3.990 693.240 1058.810 694.640 ;
        RECT 3.990 687.840 1059.210 693.240 ;
        RECT 4.400 686.440 1059.210 687.840 ;
        RECT 3.990 660.640 1059.210 686.440 ;
        RECT 3.990 659.240 1058.810 660.640 ;
        RECT 3.990 653.840 1059.210 659.240 ;
        RECT 4.400 652.440 1059.210 653.840 ;
        RECT 3.990 626.640 1059.210 652.440 ;
        RECT 3.990 625.240 1058.810 626.640 ;
        RECT 3.990 616.440 1059.210 625.240 ;
        RECT 4.400 615.040 1059.210 616.440 ;
        RECT 3.990 592.640 1059.210 615.040 ;
        RECT 3.990 591.240 1058.810 592.640 ;
        RECT 3.990 582.440 1059.210 591.240 ;
        RECT 4.400 581.040 1059.210 582.440 ;
        RECT 3.990 558.640 1059.210 581.040 ;
        RECT 3.990 557.240 1058.810 558.640 ;
        RECT 3.990 548.440 1059.210 557.240 ;
        RECT 4.400 547.040 1059.210 548.440 ;
        RECT 3.990 524.640 1059.210 547.040 ;
        RECT 3.990 523.240 1058.810 524.640 ;
        RECT 3.990 514.440 1059.210 523.240 ;
        RECT 4.400 513.040 1059.210 514.440 ;
        RECT 3.990 490.640 1059.210 513.040 ;
        RECT 3.990 489.240 1058.810 490.640 ;
        RECT 3.990 480.440 1059.210 489.240 ;
        RECT 4.400 479.040 1059.210 480.440 ;
        RECT 3.990 456.640 1059.210 479.040 ;
        RECT 3.990 455.240 1058.810 456.640 ;
        RECT 3.990 446.440 1059.210 455.240 ;
        RECT 4.400 445.040 1059.210 446.440 ;
        RECT 3.990 419.240 1059.210 445.040 ;
        RECT 3.990 417.840 1058.810 419.240 ;
        RECT 3.990 412.440 1059.210 417.840 ;
        RECT 4.400 411.040 1059.210 412.440 ;
        RECT 3.990 385.240 1059.210 411.040 ;
        RECT 3.990 383.840 1058.810 385.240 ;
        RECT 3.990 378.440 1059.210 383.840 ;
        RECT 4.400 377.040 1059.210 378.440 ;
        RECT 3.990 351.240 1059.210 377.040 ;
        RECT 3.990 349.840 1058.810 351.240 ;
        RECT 3.990 344.440 1059.210 349.840 ;
        RECT 4.400 343.040 1059.210 344.440 ;
        RECT 3.990 317.240 1059.210 343.040 ;
        RECT 3.990 315.840 1058.810 317.240 ;
        RECT 3.990 307.040 1059.210 315.840 ;
        RECT 4.400 305.640 1059.210 307.040 ;
        RECT 3.990 283.240 1059.210 305.640 ;
        RECT 3.990 281.840 1058.810 283.240 ;
        RECT 3.990 273.040 1059.210 281.840 ;
        RECT 4.400 271.640 1059.210 273.040 ;
        RECT 3.990 249.240 1059.210 271.640 ;
        RECT 3.990 247.840 1058.810 249.240 ;
        RECT 3.990 239.040 1059.210 247.840 ;
        RECT 4.400 237.640 1059.210 239.040 ;
        RECT 3.990 215.240 1059.210 237.640 ;
        RECT 3.990 213.840 1058.810 215.240 ;
        RECT 3.990 205.040 1059.210 213.840 ;
        RECT 4.400 203.640 1059.210 205.040 ;
        RECT 3.990 181.240 1059.210 203.640 ;
        RECT 3.990 179.840 1058.810 181.240 ;
        RECT 3.990 171.040 1059.210 179.840 ;
        RECT 4.400 169.640 1059.210 171.040 ;
        RECT 3.990 147.240 1059.210 169.640 ;
        RECT 3.990 145.840 1058.810 147.240 ;
        RECT 3.990 137.040 1059.210 145.840 ;
        RECT 4.400 135.640 1059.210 137.040 ;
        RECT 3.990 109.840 1059.210 135.640 ;
        RECT 3.990 108.440 1058.810 109.840 ;
        RECT 3.990 103.040 1059.210 108.440 ;
        RECT 4.400 101.640 1059.210 103.040 ;
        RECT 3.990 75.840 1059.210 101.640 ;
        RECT 3.990 74.440 1058.810 75.840 ;
        RECT 3.990 69.040 1059.210 74.440 ;
        RECT 4.400 67.640 1059.210 69.040 ;
        RECT 3.990 41.840 1059.210 67.640 ;
        RECT 3.990 40.440 1058.810 41.840 ;
        RECT 3.990 35.040 1059.210 40.440 ;
        RECT 4.400 33.640 1059.210 35.040 ;
        RECT 3.990 7.840 1059.210 33.640 ;
        RECT 3.990 6.975 1058.810 7.840 ;
      LAYER met4 ;
        RECT 320.455 249.055 327.840 1059.945 ;
        RECT 330.240 249.055 331.140 1059.945 ;
        RECT 333.540 249.055 481.440 1059.945 ;
        RECT 483.840 249.055 484.740 1059.945 ;
        RECT 487.140 249.055 635.040 1059.945 ;
        RECT 637.440 249.055 638.340 1059.945 ;
        RECT 640.740 249.055 704.425 1059.945 ;
  END
END combinational_multiplier_32x32
END LIBRARY

